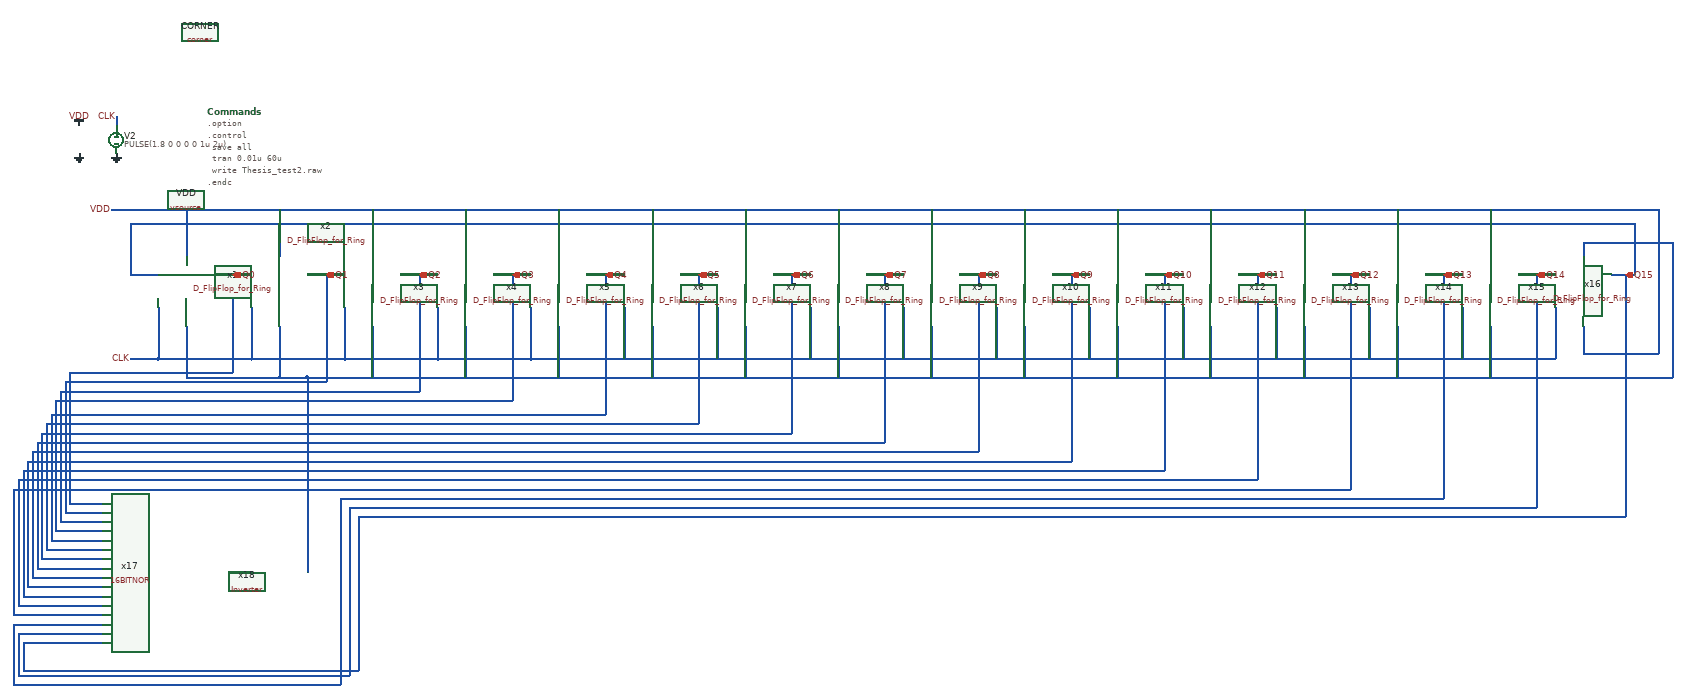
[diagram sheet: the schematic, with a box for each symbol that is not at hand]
v {xschem version=3.4.6RC file_version=1.2
}
G {}
K {}
V {}
S {}
E {}
N -1550 -90 -1550 20 {
lab=CLK}
N -1350 -90 -1350 20 {
lab=CLK}
N -1610 20 -1550 20 {
lab=CLK}
N -1550 20 -1350 20 {
lab=CLK}
N -1150 -90 -1150 20 {
lab=CLK}
N -1350 20 -1150 20 {
lab=CLK}
N -950 -90 -950 20 {
lab=CLK}
N -1150 20 -950 20 {
lab=CLK}
N -750 -90 -750 20 {
lab=CLK}
N -950 20 -750 20 {
lab=CLK}
N -550 -90 -550 20 {
lab=CLK}
N -350 -90 -350 20 {
lab=CLK}
N -150 -90 -150 20 {
lab=CLK}
N 50 -90 50 20 {
lab=CLK}
N 250 -90 250 20 {
lab=CLK}
N 450 -90 450 20 {
lab=CLK}
N 650 -90 650 20 {
lab=CLK}
N 850 -90 850 20 {
lab=CLK}
N 1050 -90 1050 20 {
lab=CLK}
N 1250 -90 1250 20 {
lab=CLK}
N 1450 -90 1450 20 {
lab=CLK}
N -750 20 1450 20 {
lab=CLK}
N -1430 -160 -1350 -160 {
lab=Q0}
N -1230 -160 -1150 -160 {
lab=Q1}
N -1030 -160 -950 -160 {
lab=Q2}
N -830 -160 -750 -160 {
lab=Q3}
N -630 -160 -550 -160 {
lab=Q4}
N -430 -160 -350 -160 {
lab=Q5}
N -230 -160 -150 -160 {
lab=Q6}
N -30 -160 50 -160 {
lab=Q7}
N 170 -160 250 -160 {
lab=Q8}
N 370 -160 450 -160 {
lab=Q9}
N 570 -160 650 -160 {
lab=Q10}
N 770 -160 850 -160 {
lab=Q11}
N 970 -160 1050 -160 {
lab=Q12}
N 1170 -160 1250 -160 {
lab=Q13}
N 1370 -160 1450 -160 {
lab=Q14}
N 1570 -160 1620 -160 {
lab=Q15}
N 1620 -270 1620 -160 {
lab=Q15}
N -1610 -270 1620 -270 {
lab=Q15}
N -1490 -240 -1490 -200 {
lab=VDD}
N -1290 -300 -1290 -200 {
lab=VDD}
N -1090 -300 -1090 -200 {
lab=VDD}
N -890 -300 -890 -200 {
lab=VDD}
N -690 -300 -690 -200 {
lab=VDD}
N -490 -300 -490 -200 {
lab=VDD}
N -290 -300 -290 -200 {
lab=VDD}
N -90 -300 -90 -200 {
lab=VDD}
N 110 -300 110 -200 {
lab=VDD}
N 310 -300 310 -200 {
lab=VDD}
N 510 -300 510 -200 {
lab=VDD}
N 710 -300 710 -200 {
lab=VDD}
N 910 -300 910 -200 {
lab=VDD}
N 1110 -300 1110 -200 {
lab=VDD}
N 1310 -300 1310 -200 {
lab=VDD}
N -1640 -500 -1640 -480 {
lab=CLK}
N -1590 -300 1510 -300 {
lab=VDD}
N -1610 -300 -1590 -300 {
lab=VDD}
N -1610 -270 -1610 -160 {
lab=Q15}
N -1610 -160 -1550 -160 {
lab=Q15}
N -1390 -160 -1390 50 {
lab=Q0}
N -1650 -300 -1610 -300 {
lab=VDD}
N 410 -160 410 230 {
lab=Q9}
N 610 -160 610 230 {
lab=Q10}
N 810 -160 810 230 {
lab=Q11}
N 1010 -160 1010 230 {
lab=Q12}
N 1210 -160 1210 230 {
lab=Q13}
N 1410 -160 1410 230 {
lab=Q14}
N 1600 -160 1600 230 {
lab=Q15}
N -1290 -50 -1290 -20 {
lab=#net1}
N -1090 -50 -1090 -30 {
lab=#net1}
N -890 -50 -890 -20 {
lab=#net1}
N -1090 -30 -1090 -20 {
lab=#net1}
N -690 -50 -690 -30 {
lab=#net1}
N -490 -50 -490 -30 {
lab=#net1}
N -290 -50 -290 -30 {
lab=#net1}
N -90 -50 -90 -30 {
lab=#net1}
N 110 -50 110 -30 {
lab=#net1}
N 310 -50 310 -40 {
lab=#net1}
N 510 -50 510 -40 {
lab=#net1}
N 710 -50 710 -40 {
lab=#net1}
N 910 -50 910 -40 {
lab=#net1}
N 1110 -50 1110 -40 {
lab=#net1}
N -1740 50 -1390 50 {
lab=Q0}
N -1740 50 -1740 330 {
lab=Q0}
N -1740 330 -1670 330 {
lab=Q0}
N -1370 480 -1350 480 {
lab=#net2}
N -1230 60 -1230 480 {
lab=#net1}
N -1290 60 -1230 60 {
lab=#net1}
N -1290 -20 -1290 60 {
lab=#net1}
N -1190 -160 -1190 70 {
lab=Q1}
N -1750 70 -1190 70 {
lab=Q1}
N -1750 70 -1750 350 {
lab=Q1}
N -1750 350 -1670 350 {
lab=Q1}
N -1760 370 -1670 370 {
lab=Q2}
N -1760 90 -1760 370 {
lab=Q2}
N -1760 90 -1090 90 {
lab=Q2}
N -1770 390 -1670 390 {
lab=Q3}
N -1770 110 -1770 390 {
lab=Q3}
N -1770 110 -990 110 {
lab=Q3}
N -1780 410 -1670 410 {
lab=Q4}
N -1780 140 -1780 410 {
lab=Q4}
N -1780 140 -890 140 {
lab=Q4}
N -890 140 -790 140 {
lab=Q4}
N -1090 90 -990 90 {
lab=Q2}
N -990 -160 -990 90 {
lab=Q2}
N -990 110 -790 110 {
lab=Q3}
N -790 -160 -790 110 {
lab=Q3}
N -790 140 -590 140 {
lab=Q4}
N -590 -160 -590 140 {
lab=Q4}
N -1790 430 -1670 430 {
lab=Q5}
N -1790 160 -1790 430 {
lab=Q5}
N -1790 160 -390 160 {
lab=Q5}
N -390 -160 -390 160 {
lab=Q5}
N -1800 450 -1670 450 {
lab=Q6}
N -1800 180 -1800 450 {
lab=Q6}
N -1800 180 -190 180 {
lab=Q6}
N -190 -160 -190 180 {
lab=Q6}
N -1810 470 -1670 470 {
lab=Q7}
N -1810 200 -1810 470 {
lab=Q7}
N -1810 200 10 200 {
lab=Q7}
N -1820 490 -1670 490 {
lab=Q8}
N -1820 220 -1820 490 {
lab=Q8}
N -1820 220 210 220 {
lab=Q8}
N 10 -160 10 200 {
lab=Q7}
N 210 -160 210 220 {
lab=Q8}
N -1830 510 -1670 510 {
lab=Q9}
N -1830 240 -1830 510 {
lab=Q9}
N -1830 240 410 240 {
lab=Q9}
N 410 230 410 240 {
lab=Q9}
N -1840 530 -1670 530 {
lab=Q10}
N -1840 260 -1840 530 {
lab=Q10}
N -1840 260 610 260 {
lab=Q10}
N 610 230 610 260 {
lab=Q10}
N -1850 550 -1670 550 {
lab=Q11}
N -1850 280 -1850 550 {
lab=Q11}
N -1850 280 810 280 {
lab=Q11}
N 810 230 810 280 {
lab=Q11}
N -1860 570 -1670 570 {
lab=Q12}
N -1860 300 -1860 570 {
lab=Q12}
N -1860 300 1010 300 {
lab=Q12}
N 1010 230 1010 300 {
lab=Q12}
N -1860 590 -1670 590 {
lab=Q13}
N -1860 590 -1860 720 {
lab=Q13}
N -1860 720 -1160 720 {
lab=Q13}
N -1160 320 -1160 720 {
lab=Q13}
N -1160 320 1210 320 {
lab=Q13}
N 1210 230 1210 320 {
lab=Q13}
N -1850 610 -1670 610 {
lab=Q14}
N -1850 610 -1850 700 {
lab=Q14}
N -1850 700 -1140 700 {
lab=Q14}
N -1140 340 -1140 700 {
lab=Q14}
N -1140 340 1410 340 {
lab=Q14}
N 1410 230 1410 340 {
lab=Q14}
N -1840 630 -1670 630 {
lab=Q15}
N -1840 630 -1840 690 {
lab=Q15}
N -1840 690 -1120 690 {
lab=Q15}
N -1120 360 -1120 690 {
lab=Q15}
N -1120 360 1600 360 {
lab=Q15}
N 1600 230 1600 360 {
lab=Q15}
N -1090 -20 -1090 60 {
lab=#net1}
N -890 -20 -890 60 {
lab=#net1}
N -690 -30 -690 60 {
lab=#net1}
N -490 -30 -490 60 {
lab=#net1}
N -290 -30 -290 60 {
lab=#net1}
N -90 -30 -90 60 {
lab=#net1}
N 110 -30 110 60 {
lab=#net1}
N 310 -40 310 60 {
lab=#net1}
N 510 -40 510 60 {
lab=#net1}
N 710 -40 710 60 {
lab=#net1}
N 910 -40 910 60 {
lab=#net1}
N 1110 -40 1110 60 {
lab=#net1}
N 1310 -50 1310 60 {
lab=#net1}
N -1230 60 1510 60 {
lab=#net1}
N -1490 60 -1290 60 {
lab=#net1}
N -1490 -50 -1490 0 {
lab=#net1}
N -1490 0 -1490 60 {
lab=#net1}
N -1490 -300 -1490 -240 {
lab=VDD}
N 1510 60 1700 60 {
lab=#net1}
N 1700 -230 1700 60 {
lab=#net1}
N 1510 -230 1700 -230 {
lab=#net1}
N 1510 -230 1510 -200 {
lab=#net1}
N 1510 -50 1510 10 {
lab=VDD}
N 1510 10 1670 10 {
lab=VDD}
N 1670 -300 1670 10 {
lab=VDD}
N 1510 -300 1670 -300 {
lab=VDD}
C {D_FlipFlop_for_Ring.sym} -1450 0 0 0 {name=x1}
C {D_FlipFlop_for_Ring.sym} -1250 0 0 0 {name=x2}
C {D_FlipFlop_for_Ring.sym} -1050 0 0 0 {name=x3}
C {D_FlipFlop_for_Ring.sym} -850 0 0 0 {name=x4}
C {D_FlipFlop_for_Ring.sym} -650 0 0 0 {name=x5}
C {D_FlipFlop_for_Ring.sym} -450 0 0 0 {name=x6}
C {D_FlipFlop_for_Ring.sym} -250 0 0 0 {name=x7}
C {D_FlipFlop_for_Ring.sym} -50 0 0 0 {name=x8}
C {D_FlipFlop_for_Ring.sym} 150 0 0 0 {name=x9}
C {D_FlipFlop_for_Ring.sym} 350 0 0 0 {name=x10}
C {D_FlipFlop_for_Ring.sym} 550 0 0 0 {name=x11}
C {D_FlipFlop_for_Ring.sym} 750 0 0 0 {name=x12}
C {D_FlipFlop_for_Ring.sym} 950 0 0 0 {name=x13}
C {D_FlipFlop_for_Ring.sym} 1150 0 0 0 {name=x14}
C {D_FlipFlop_for_Ring.sym} 1350 0 0 0 {name=x15}
C {D_FlipFlop_for_Ring.sym} 1550 0 0 0 {name=x16}
C {opin.sym} -1390 -160 3 0 {name=p11 lab=Q0}
C {opin.sym} -1190 -160 3 0 {name=p1 lab=Q1}
C {opin.sym} -990 -160 3 0 {name=p2 lab=Q2}
C {opin.sym} -790 -160 3 0 {name=p3 lab=Q3}
C {opin.sym} -590 -160 3 0 {name=p4 lab=Q4}
C {opin.sym} -390 -160 3 0 {name=p5 lab=Q5}
C {opin.sym} -190 -160 3 0 {name=p6 lab=Q6}
C {opin.sym} 10 -160 3 0 {name=p7 lab=Q7}
C {opin.sym} 210 -160 3 0 {name=p8 lab=Q8}
C {opin.sym} 410 -160 3 0 {name=p9 lab=Q9}
C {opin.sym} 610 -160 3 0 {name=p10 lab=Q10}
C {opin.sym} 810 -160 3 0 {name=p12 lab=Q11}
C {opin.sym} 1010 -160 3 0 {name=p13 lab=Q12}
C {opin.sym} 1210 -160 3 0 {name=p14 lab=Q13}
C {opin.sym} 1410 -160 3 0 {name=p15 lab=Q14}
C {opin.sym} 1600 -160 3 0 {name=p16 lab=Q15}
C {lab_wire.sym} -1650 -300 0 0 {name=p17 sig_type=std_logic lab=VDD
value=0}
C {lab_wire.sym} -1610 20 0 0 {name=p18 sig_type=std_logic lab=CLK
value=0}
C {gnd.sym} -1640 -420 0 0 {name=l27 lab=GND
value=1.8}
C {lab_wire.sym} -1640 -500 0 0 {name=p20 sig_type=std_logic lab=CLK
value=1.8}
C {vsource.sym} -1640 -450 0 0 {name=V2 value="PULSE(1.8 0 0 0 0 1u 2u)" savecurrent=false}
C {code_shown.sym} -1445 -510 0 0 {name=Commands only_toplevel=false value="
.option 
.control
  save all
  tran 0.01u 60u
  write Thesis_test2.raw
  
.endc
"}
C {vsource.sym} -1720 -450 0 0 {name=VDD value=1.8 savecurrent=false}
C {gnd.sym} -1720 -420 0 0 {name=l17 lab=GND}
C {vdd.sym} -1720 -480 0 0 {name=l18 lab=VDD}
C {sky130_fd_pr/corner.sym} -1460 -680 0 0 {name=CORNER only_toplevel=true corner=tt}
C {16BITNOR.sym} -1540 480 0 0 {name=x17}
C {Inverter.sym} -1300 520 0 0 {name=x18}
